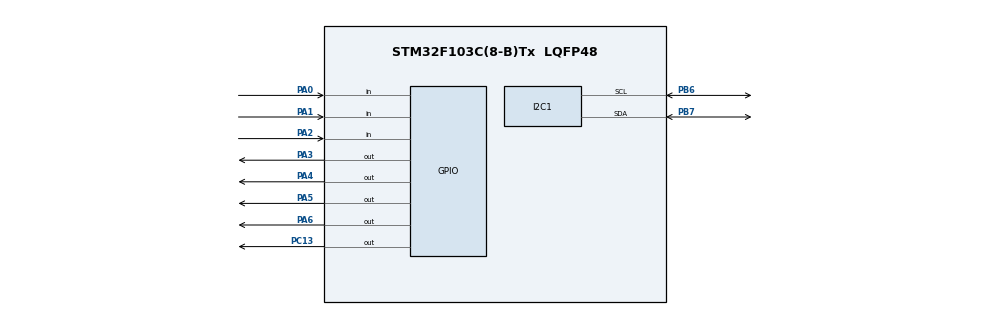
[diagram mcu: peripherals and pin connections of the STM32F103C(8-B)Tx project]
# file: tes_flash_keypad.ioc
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Mcu.Family=STM32F1
Mcu.Name=STM32F103C(8-B)Tx
Mcu.Package=LQFP48
NVIC.PriorityGroup=NVIC_PRIORITYGROUP_4
PA0-WKUP.Signal=GPIO_Input
PA1.Signal=GPIO_Input
PA13.Mode=Serial_Wire
PA13.Signal=SYS_JTMS-SWDIO
PA14.Mode=Serial_Wire
PA14.Signal=SYS_JTCK-SWCLK
PA2.Signal=GPIO_Input
PA3.Signal=GPIO_Output
PA4.Signal=GPIO_Output
PA5.Signal=GPIO_Output
PA6.Signal=GPIO_Output
PB6.Mode=I2C
PB6.Signal=I2C1_SCL
PB7.Mode=I2C
PB7.Signal=I2C1_SDA
PC13-TAMPER-RTC.Signal=GPIO_Output
PD0-OSC_IN.Mode=HSE-External-Oscillator
PD0-OSC_IN.Signal=RCC_OSC_IN
PD1-OSC_OUT.Mode=HSE-External-Oscillator
PD1-OSC_OUT.Signal=RCC_OSC_OUT
ProjectManager.HeapSize=0x200
ProjectManager.StackSize=0x400
ProjectManager.TargetToolchain=STM32CubeIDE
RCC.APB1Freq_Value=8000000
RCC.APB2Freq_Value=8000000
board=custom

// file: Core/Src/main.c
/* USER CODE BEGIN Header */
/**
  ******************************************************************************
  * @file           : main.c
  * @brief          : Main program body
  ******************************************************************************
  * @attention
  *
  * Copyright (c) 2023 STMicroelectronics.
  * All rights reserved.
  *
  * This software is licensed under terms that can be found in the LICENSE file
  * in the root directory of this software component.
  * If no LICENSE file comes with this software, it is provided AS-IS.
  *
  ******************************************************************************
  */
/* USER CODE END Header */
#include "main.h"

/* USER CODE BEGIN Includes */
#include "api_keypad.h"
/* USER CODE END Includes */

/* USER CODE BEGIN PTD */
//uint8_t x = 0;
//uint8_t y = 0;
/* USER CODE END PTD */

I2C_HandleTypeDef hi2c1;

/* USER CODE BEGIN PV */
uint8_t key;
uint8_t key_check = '*';
uint8_t str[4];
/* USER CODE END PV */

void SystemClock_Config(void);
static void MX_GPIO_Init(void);
static void MX_I2C1_Init(void);

int main(void) {

	/* MCU Configuration--------------------------------------------------------*/

	/* Reset of all peripherals, Initializes the Flash interface and the Systick. */
	HAL_Init();

	/* Configure the system clock */
	SystemClock_Config();

	/* Initialize all configured peripherals */
	MX_GPIO_Init();
	MX_I2C1_Init();
	/* USER CODE BEGIN 2 */
	keypad_name keypad;
	api_keypad_init(&keypad, GPIOA, GPIO_PIN_0, GPIOA, GPIO_PIN_1,
							 GPIOA,	GPIO_PIN_2, GPIOA, GPIO_PIN_3,
							 GPIOA, GPIO_PIN_4, GPIOA, GPIO_PIN_5,
							 GPIOA, GPIO_PIN_6);
	lcd_init(&hi2c1);
	/* USER CODE END 2 */

	/* Infinite loop */
	while (1) {

		/* USER CODE BEGIN 3 */
	// this code line use to test api
	if (api_check_have_button(&keypad)) {
		if (api_check_button(&keypad, key_check)) {
			if (api_enter_pass(&keypad, str)) {
				// xu ly tiep theo trong truong hop nhap du 4 ky tu
				lcd_send_string("sucessful");
				HAL_Delay(500);
			} else {

				lcd_send_string("time out");
				HAL_Delay(500);
			}
		}
	}
	lcd_clear();
		/* USER CODE END 3 */
	}
}

void SystemClock_Config(void)
{
  RCC_OscInitTypeDef RCC_OscInitStruct = {0};
  RCC_ClkInitTypeDef RCC_ClkInitStruct = {0};

  /** Initializes the RCC Oscillators according to the specified parameters
  * in the RCC_OscInitTypeDef structure.
  */
  RCC_OscInitStruct.OscillatorType = RCC_OSCILLATORTYPE_HSE;
  RCC_OscInitStruct.HSEState = RCC_HSE_ON;
  RCC_OscInitStruct.HSEPredivValue = RCC_HSE_PREDIV_DIV1;
  RCC_OscInitStruct.HSIState = RCC_HSI_ON;
  RCC_OscInitStruct.PLL.PLLState = RCC_PLL_ON;
  RCC_OscInitStruct.PLL.PLLSource = RCC_PLLSOURCE_HSE;
  RCC_OscInitStruct.PLL.PLLMUL = RCC_PLL_MUL9;
  if (HAL_RCC_OscConfig(&RCC_OscInitStruct) != HAL_OK)
  {
    Error_Handler();
  }

  /** Initializes the CPU, AHB and APB buses clocks
  */
  RCC_ClkInitStruct.ClockType = RCC_CLOCKTYPE_HCLK|RCC_CLOCKTYPE_SYSCLK
                              |RCC_CLOCKTYPE_PCLK1|RCC_CLOCKTYPE_PCLK2;
  RCC_ClkInitStruct.SYSCLKSource = RCC_SYSCLKSOURCE_PLLCLK;
  RCC_ClkInitStruct.AHBCLKDivider = RCC_SYSCLK_DIV1;
  RCC_ClkInitStruct.APB1CLKDivider = RCC_HCLK_DIV2;
  RCC_ClkInitStruct.APB2CLKDivider = RCC_HCLK_DIV1;

  if (HAL_RCC_ClockConfig(&RCC_ClkInitStruct, FLASH_LATENCY_2) != HAL_OK)
  {
    Error_Handler();
  }
}

static void MX_I2C1_Init(void)
{

  hi2c1.Instance = I2C1;
  hi2c1.Init.ClockSpeed = 100000;
  hi2c1.Init.DutyCycle = I2C_DUTYCYCLE_2;
  hi2c1.Init.OwnAddress1 = 0;
  hi2c1.Init.AddressingMode = I2C_ADDRESSINGMODE_7BIT;
  hi2c1.Init.DualAddressMode = I2C_DUALADDRESS_DISABLE;
  hi2c1.Init.OwnAddress2 = 0;
  hi2c1.Init.GeneralCallMode = I2C_GENERALCALL_DISABLE;
  hi2c1.Init.NoStretchMode = I2C_NOSTRETCH_DISABLE;
  if (HAL_I2C_Init(&hi2c1) != HAL_OK)
  {
    Error_Handler();
  }

}

static void MX_GPIO_Init(void)
{
  GPIO_InitTypeDef GPIO_InitStruct = {0};

  /* GPIO Ports Clock Enable */
  __HAL_RCC_GPIOC_CLK_ENABLE();
  __HAL_RCC_GPIOD_CLK_ENABLE();
  __HAL_RCC_GPIOA_CLK_ENABLE();
  __HAL_RCC_GPIOB_CLK_ENABLE();

  /*Configure GPIO pin Output Level */
  HAL_GPIO_WritePin(GPIOC, GPIO_PIN_13, GPIO_PIN_RESET);

  /*Configure GPIO pin Output Level */
  HAL_GPIO_WritePin(GPIOA, GPIO_PIN_3|GPIO_PIN_4|GPIO_PIN_5|GPIO_PIN_6, GPIO_PIN_RESET);

  /*Configure GPIO pin : PC13 */
  GPIO_InitStruct.Pin = GPIO_PIN_13;
  GPIO_InitStruct.Mode = GPIO_MODE_OUTPUT_PP;
  GPIO_InitStruct.Pull = GPIO_NOPULL;
  GPIO_InitStruct.Speed = GPIO_SPEED_FREQ_LOW;
  HAL_GPIO_Init(GPIOC, &GPIO_InitStruct);

  /*Configure GPIO pins : PA0 PA1 PA2 */
  GPIO_InitStruct.Pin = GPIO_PIN_0|GPIO_PIN_1|GPIO_PIN_2;
  GPIO_InitStruct.Mode = GPIO_MODE_INPUT;
  GPIO_InitStruct.Pull = GPIO_PULLUP;
  HAL_GPIO_Init(GPIOA, &GPIO_InitStruct);

  /*Configure GPIO pins : PA3 PA4 PA5 PA6 */
  GPIO_InitStruct.Pin = GPIO_PIN_3|GPIO_PIN_4|GPIO_PIN_5|GPIO_PIN_6;
  GPIO_InitStruct.Mode = GPIO_MODE_OUTPUT_PP;
  GPIO_InitStruct.Pull = GPIO_NOPULL;
  GPIO_InitStruct.Speed = GPIO_SPEED_FREQ_LOW;
  HAL_GPIO_Init(GPIOA, &GPIO_InitStruct);

}

void Error_Handler(void)
{
  __disable_irq();
  while (1)
  {
  }
}
